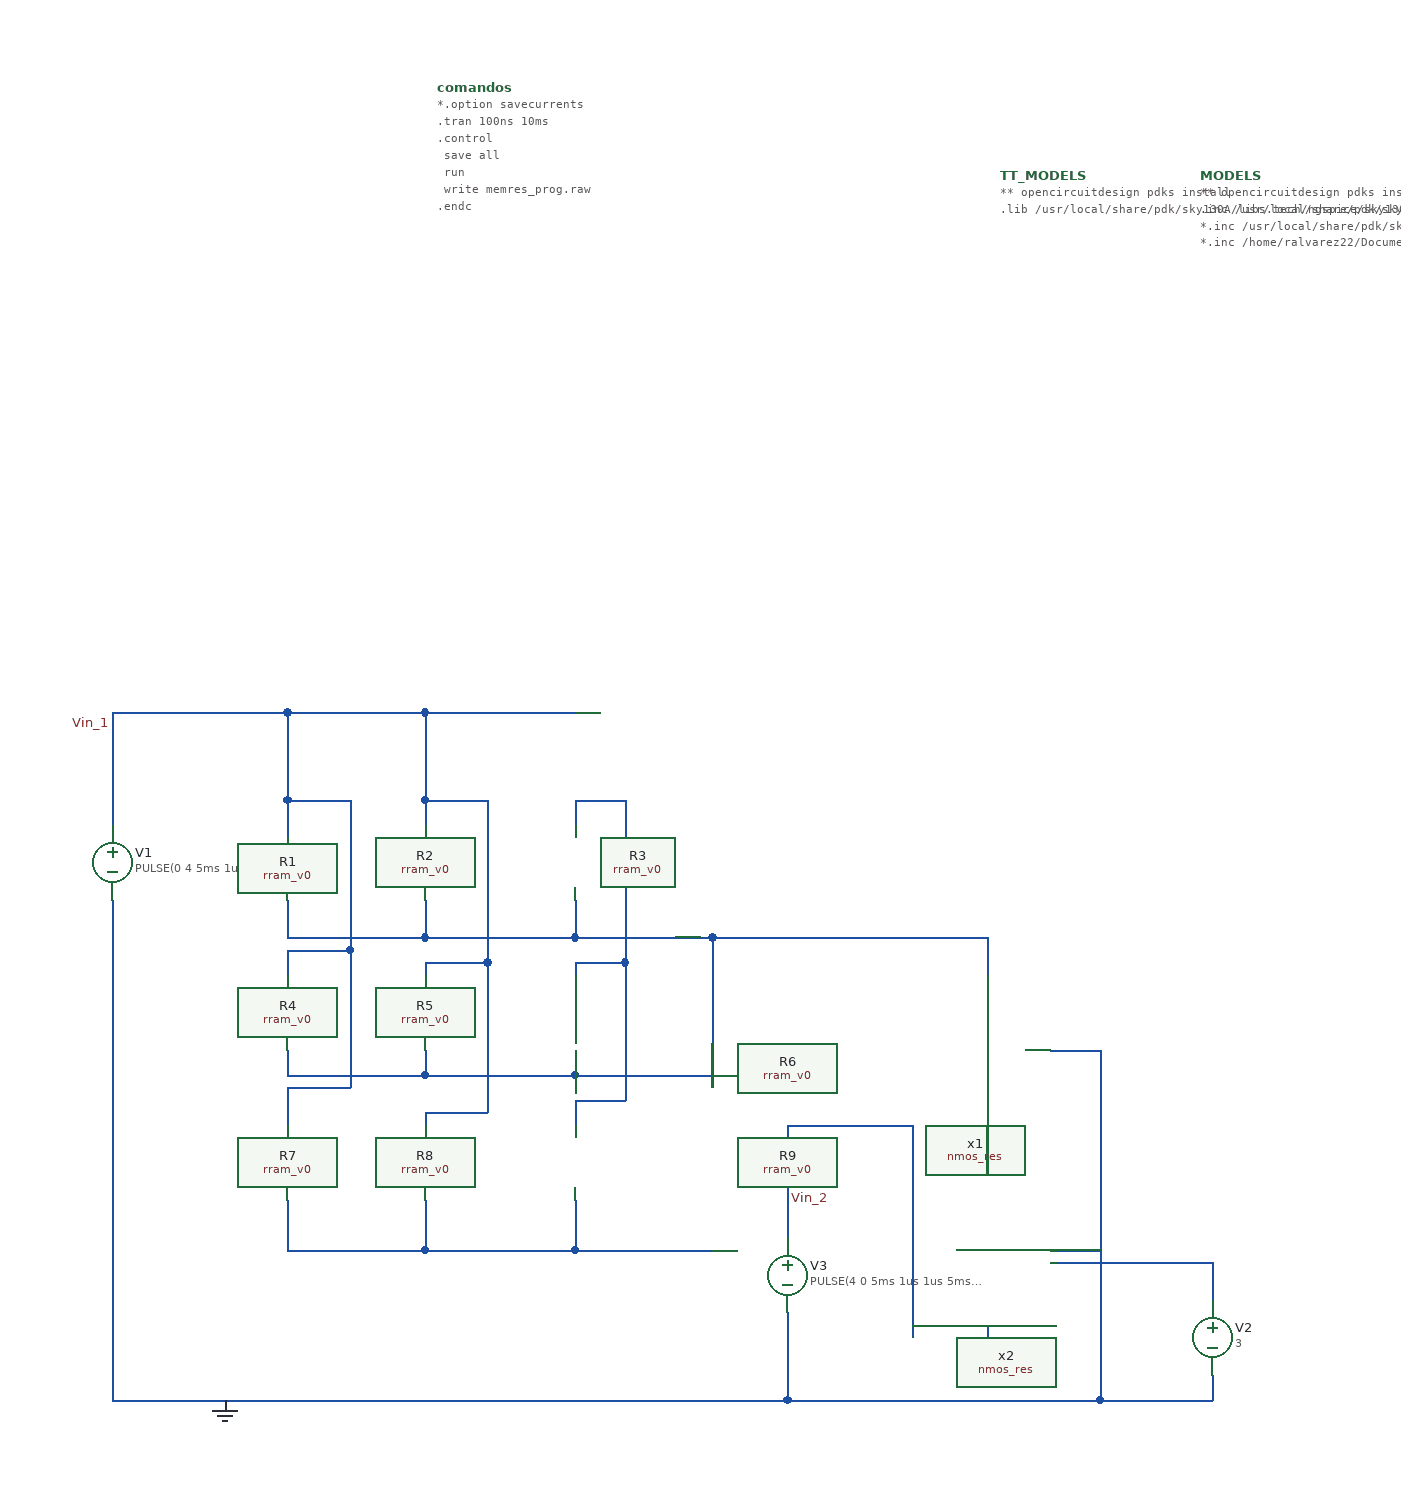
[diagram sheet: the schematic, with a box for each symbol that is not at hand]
v {xschem version=3.4.5 file_version=1.2
}
G {}
K {}
V {}
S {}
E {}
B 2 625 -450 1425 -50 {flags=graph
y1=-6.5862747
y2=9.2820444
ypos1=0
ypos2=2
divy=5
subdivy=1
unity=1
x1=0.0030438397
x2=0.0074760572
divx=5
subdivx=1
xlabmag=1.0
ylabmag=1.0


dataset=-1
unitx=1
logx=0
logy=0


















sweep=time
color="4 15"
node="\\"VSource_1;vin_1\\"
\\"VSource_2;vin_2\\""}
B 2 630 0 1475 405 {flags=graph
y1=28907.679
y2=33556.258
ypos1=0
ypos2=2
divy=5
subdivy=1
unity=1
x1=0.0030438397
x2=0.0074760572
divx=5
subdivx=1
xlabmag=1.0
ylabmag=1.0


dataset=-1
unitx=1
logx=0
logy=0


















sweep=time

color=10
node="\\"mem_2;n.xr2.n1#ngap -1 * i(v1) /\\""
rainbow=0}
B 2 1570 0 2415 405 {flags=graph
y1=8203.3521
y2=32255.17
ypos1=0
ypos2=2
divy=5
subdivy=1
unity=1
x1=0.0030438397
x2=0.0074760572
divx=5
subdivx=1
xlabmag=1.0
ylabmag=1.0


dataset=-1
unitx=1
logx=0
logy=0


















sweep=time

color=12
node="\\"mem_5;n.xr5.n1#ngap -1 * i(v1) /\\""
rainbow=0}
B 2 870 450 1715 855 {flags=graph
y1=20638.255
y2=25717.835
ypos1=0
ypos2=2
divy=5
subdivy=1
unity=1
x1=0.0030438397
x2=0.0074760572
divx=5
subdivx=1
xlabmag=1.0
ylabmag=1.0


dataset=-1
unitx=1
logx=0
logy=0


















sweep=time

color=8
node="\\"mem_8;n.xr8.n1#ngap -1 * i(v1) /\\""
rainbow=0}
B 2 1800 450 2645 855 {flags=graph
y1=20214.819
y2=24250.045
ypos1=0
ypos2=2
divy=5
subdivy=1
unity=1
x1=0.0030438397
x2=0.0074760572
divx=5
subdivx=1
xlabmag=1.0
ylabmag=1.0


dataset=-1
unitx=1
logx=0
logy=0


















sweep=time

color=21
node="\\"mem_4;n.xr4.n1#ngap -1 * i(v1) /\\""
rainbow=0}
N -500 90 -500 110 {
lab=Vin_1}
N -390 90 -390 110 {
lab=Vin_1}
N -500 410 -500 450 {
lab=#net1}
N -390 410 -390 450 {
lab=#net1}
N -270 410 -270 450 {
lab=#net1}
N -170 200 -160 200 {
lab=#net2}
N -500 450 -390 450 {
lab=#net1}
N -390 450 -270 450 {
lab=#net1}
N -270 450 -160 450 {
lab=#net1}
N -640 20 -640 110 {
lab=Vin_1}
N -640 20 -500 20 {
lab=Vin_1}
N -500 20 -390 20 {
lab=Vin_1}
N -390 20 -270 20 {
lab=Vin_1}
N -640 170 -640 570 {
lab=GND}
N -640 570 -520 570 {
lab=GND}
N -160 200 60 200 {
lab=#net2}
N 60 200 60 230 {
lab=#net2}
N -520 570 -100 570 {
lab=GND}
N 110 290 150 290 {
lab=GND}
N 150 290 150 570 {
lab=GND}
N -100 570 150 570 {
lab=GND}
N -100 500 -100 570 {
lab=GND}
N -100 350 -100 440 {
lab=Vin_2}
N -100 350 -0 350 {
lab=Vin_2}
N -0 350 0 520 {
lab=Vin_2}
N -500 90 -450 90 {
lab=Vin_1}
N -450 90 -450 210 {
lab=Vin_1}
N -500 210 -450 210 {
lab=Vin_1}
N -500 210 -500 230 {
lab=Vin_1}
N -450 210 -450 320 {
lab=Vin_1}
N -500 320 -450 320 {
lab=Vin_1}
N -500 320 -500 350 {
lab=Vin_1}
N -390 20 -390 90 {
lab=Vin_1}
N -500 170 -500 190 {
lab=#net2}
N -500 190 -500 200 {
lab=#net2}
N -390 170 -390 200 {
lab=#net2}
N -270 170 -270 200 {
lab=#net2}
N -500 290 -500 310 {
lab=#net2}
N -390 290 -390 310 {
lab=#net2}
N -270 290 -270 310 {
lab=#net2}
N -390 90 -340 90 {
lab=Vin_1}
N -340 90 -340 220 {
lab=Vin_1}
N -390 220 -340 220 {
lab=Vin_1}
N -390 220 -390 230 {
lab=Vin_1}
N -340 220 -340 340 {
lab=Vin_1}
N -390 340 -340 340 {
lab=Vin_1}
N -390 340 -390 350 {
lab=Vin_1}
N -270 90 -230 90 {
lab=#net3}
N -230 90 -230 220 {
lab=#net3}
N -270 220 -230 220 {
lab=#net3}
N -270 220 -270 230 {
lab=#net3}
N -230 220 -230 330 {
lab=#net3}
N -270 330 -230 330 {
lab=#net3}
N -270 330 -270 350 {
lab=#net3}
N -500 310 -390 310 {
lab=#net2}
N -390 310 -270 310 {
lab=#net2}
N -270 310 -190 310 {
lab=#net2}
N -160 200 -160 320 {
lab=#net2}
N 110 460 240 460 {
lab=#net4}
N 240 460 240 490 {
lab=#net4}
N 240 550 240 570 {
lab=GND}
N 150 570 240 570 {
lab=GND}
N -500 110 -500 120 {
lab=Vin_1}
N -500 200 -390 200 {
lab=#net2}
N -390 200 -270 200 {
lab=#net2}
N -270 90 -270 110 {
lab=#net3}
N -270 200 -200 200 {
lab=#net2}
N 60 510 60 520 {
lab=Vin_2}
N -200 200 -160 200 {
lab=#net2}
N -190 310 -160 310 {
lab=#net2}
N -500 20 -500 90 {
lab=Vin_1}
N 0 510 60 510 {
lab=Vin_2}
N 110 450 150 450 {
lab=GND}
N 60 350 60 390 {
lab=#net5}
C {devices/code_shown.sym} -380 -480 0 0 {name=comandos
only_toplevel=true
value="
*.option savecurrents 
.tran 100ns 10ms
.control
	save all
	run
	write memres_prog.raw
.endc

"}
C {devices/code.sym} 70 -410 0 0 {name=TT_MODELS
only_toplevel=true
format="tcleval( @value )"
value="
** opencircuitdesign pdks install
.lib /usr/local/share/pdk/sky130A/libs.tech/ngspice/sky130.lib.spice tt
"
spice_ignore=false}
C {devices/code.sym} 230 -410 0 0 {name=MODELS
only_toplevel=true
format="tcleval( @value )"
value="
** opencircuitdesign pdks install
.inc /usr/local/share/pdk/sky130B/libs.tech/ngspice/rram_v0.spice
*.inc /usr/local/share/pdk/sky130B/libs.tech/ngspice/cswitch.spice
*.inc /home/ralvarez22/Documents/microse/switch/cswitch.spice
"}
C {devices/vsource.sym} -640 140 0 1 {name=V1 value="PULSE(0 4 5ms 1us 1us 5ms 10ms 1)" savecurrent=true
spice_ignore=false
*PWL(0 0 1ms 0 1.01ms -2 6ms -2 6.01ms 2 11ms 2 11.01ms 0)
*PULSE(-4 4 0 1ms 1ms 10ms 20ms)}
C {devices/launcher.sym} 680 520 0 0 {name=h17 
descr="Load waves"
tclcommand="xschem raw_read $netlist_dir/memres_prog.raw"
}
C {devices/lab_pin.sym} -640 30 0 0 {name=p1 sig_type=std_logic lab=Vin_1}
C {nmos_res.sym} -30 320 0 0 {name=x1 RESVAL=21k}
C {devices/gnd.sym} -550 570 0 0 {name=l1 lab=GND}
C {devices/vsource.sym} -100 470 0 1 {name=V3 value="PULSE(4 0 5ms 1us 1us 5ms 10ms 1)" savecurrent=true
spice_ignore=false
*PWL(0 0 1ms 0 1.01ms -2 6ms -2 6.01ms 2 11ms 2 11.01ms 0)
*PULSE(-4 4 0 1ms 1ms 10ms 20ms)}
C {devices/lab_pin.sym} -100 410 2 0 {name=p2 sig_type=std_logic lab=Vin_2}
C {devices/vsource.sym} 240 520 0 0 {name=V2 value=3 savecurrent=false}
C {/usr/local/share/pdk/sky130B/libs.tech/xschem/sky130_fd_pr/rram_v0.sym} -500 150 0 0 {name=R1
model=rram_v0
spiceprefix=X
}
C {/usr/local/share/pdk/sky130B/libs.tech/xschem/sky130_fd_pr/rram_v0.sym} -390 140 0 0 {name=R2
model=rram_v0
spiceprefix=X
}
C {/usr/local/share/pdk/sky130B/libs.tech/xschem/sky130_fd_pr/rram_v0.sym} -270 140 0 0 {name=R3
model=rram_v0
spiceprefix=X
}
C {/usr/local/share/pdk/sky130B/libs.tech/xschem/sky130_fd_pr/rram_v0.sym} -500 260 0 0 {name=R4
model=rram_v0
spiceprefix=X
}
C {/usr/local/share/pdk/sky130B/libs.tech/xschem/sky130_fd_pr/rram_v0.sym} -390 260 0 0 {name=R5
model=rram_v0
spiceprefix=X
}
C {/usr/local/share/pdk/sky130B/libs.tech/xschem/sky130_fd_pr/rram_v0.sym} -270 260 0 0 {name=R6
model=rram_v0
spiceprefix=X
}
C {/usr/local/share/pdk/sky130B/libs.tech/xschem/sky130_fd_pr/rram_v0.sym} -500 380 0 0 {name=R7
model=rram_v0
spiceprefix=X
}
C {/usr/local/share/pdk/sky130B/libs.tech/xschem/sky130_fd_pr/rram_v0.sym} -390 380 0 0 {name=R8
model=rram_v0
spiceprefix=X
}
C {/usr/local/share/pdk/sky130B/libs.tech/xschem/sky130_fd_pr/rram_v0.sym} -270 380 0 0 {name=R9
model=rram_v0
spiceprefix=X
}
C {nmos_res.sym} -30 480 0 0 {name=x2 RESVAL=9k}
